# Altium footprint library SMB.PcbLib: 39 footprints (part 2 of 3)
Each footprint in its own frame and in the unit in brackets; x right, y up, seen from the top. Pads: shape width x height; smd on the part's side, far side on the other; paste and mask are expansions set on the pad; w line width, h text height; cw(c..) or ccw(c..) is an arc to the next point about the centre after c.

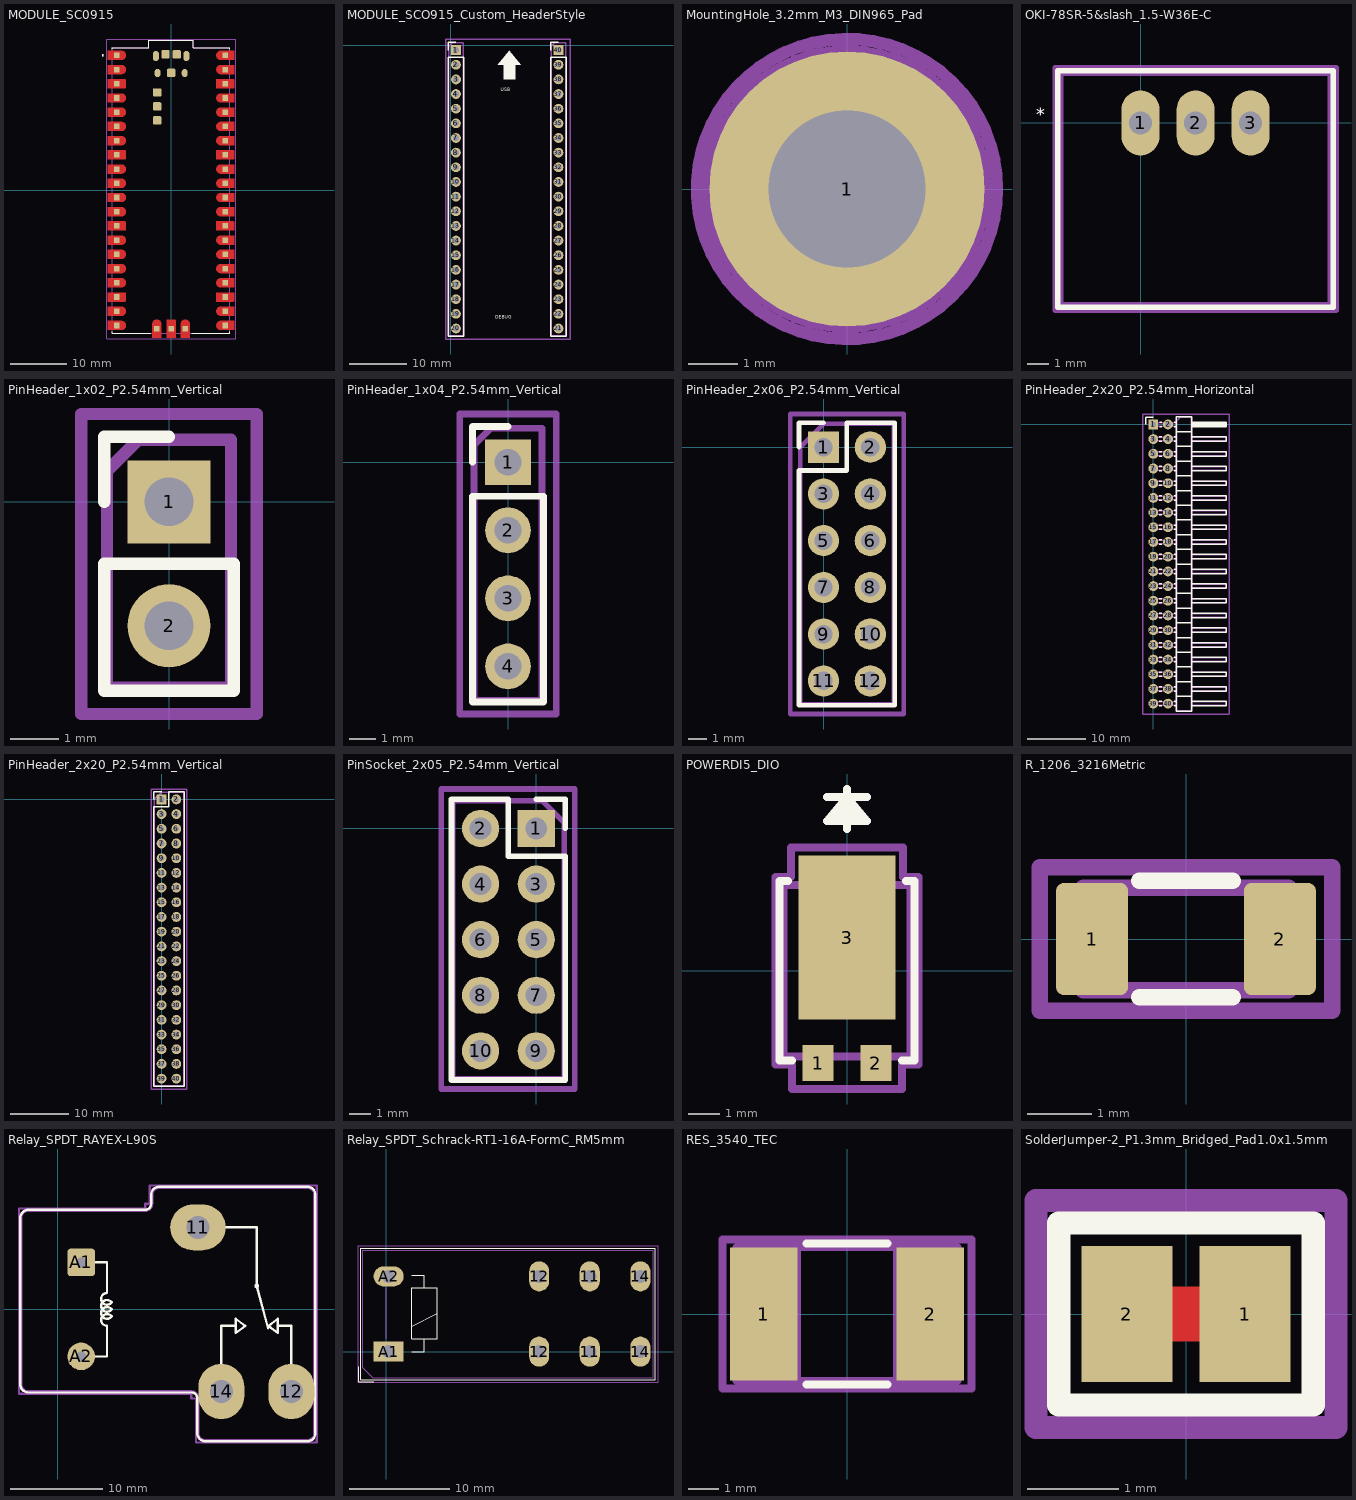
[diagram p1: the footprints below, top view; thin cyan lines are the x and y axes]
## MODULE_SC0915 [mm]
pads (53):
  rect 1x1 smd: 1(-9.69,24.13) 2(-9.69,21.59) 3(-9.69,19.05) 4(-9.69,16.51) 5(-9.69,13.97) 6(-9.69,11.43) 7(-9.69,8.89) 8(-9.69,6.35) 9(-9.69,3.81) 10(-9.69,1.27) 11(-9.69,-1.27) 12(-9.69,-3.81) 13(-9.69,-6.35) 14(-9.69,-8.89) 15(-9.69,-11.43) 16(-9.69,-13.97) 17(-9.69,-16.51) 18(-9.69,-19.05) 19(-9.69,-21.59) 20(-9.69,-24.13) 21(9.69,-24.13) 22(9.69,-21.59) 23(9.69,-19.05) 24(9.69,-16.51) 25(9.69,-13.97) 26(9.69,-11.43) 27(9.69,-8.89) 28(9.69,-6.35) 29(9.69,-3.81) 30(9.69,-1.27) 31(9.69,1.27) 32(9.69,3.81) 33(9.69,6.35) 34(9.69,8.89) 35(9.69,11.43) 36(9.69,13.97) 37(9.69,16.51) 38(9.69,19.05) 39(9.69,21.59) 40(9.69,24.13) D1(-2.54,-24.7) D2(0,-24.7) D3(2.54,-24.7)
  rrect100% 1.1x1.8 smd: A(-2.725,24) B(2.725,24)
  rrect100% 1.05x1.45 smd: C(-2.425,20.97) D(2.425,20.97)
  rrect30% 1.5x1.5 smd: TP1(0,21) TP2(1,24.3) TP3(-1,24.3) TP4(-2.5,17.5) TP5(-2.5,15) TP6(-2.5,12.5)
F.Cu:
  drawing of 43 lines, arcs and shapes, not listed
F.SilkS:
  circle w0.2: c-12.19,24.13 r0.1
  lines w0.127: -10.5,-25.25 -10.5,-25.5 -3.66,-25.5 ; -10.5,25.25 -10.5,25.5 -4,25.5 -4,26.8 4,26.8 4,25.5 10.5,25.5 10.5,25.25 ; 3.66,-25.5 10.5,-25.5 10.5,-25.25
F.Paste:
  drawing of 43 lines, arcs and shapes, not listed
F.Mask:
  drawing of 43 lines, arcs and shapes, not listed
F.Fab:
  circle w0.2: c-12.19,24.13 r0.1
  lines w0.127: -10.5,-25.5 10.5,-25.5 10.5,25.5 4,25.5 4,26.8 -4,26.8 -4,25.5 -10.5,25.5 -10.5,-25.5
F.CrtYd:
  lines w0.05: -11.54,-26.55 -11.54,27.05 11.54,27.05 11.54,-26.55 -11.54,-26.55

## MODULE_SCO915_Custom_HeaderStyle [mm]
pads (40):
  rect 1.7x1.7 hole 1: 1(0.853,-0.859) 40(18.633,-0.859)
  rrect100% 1.7x1.7 hole 1: 2(0.853,-3.399) 3(0.875,-5.95) 4(0.853,-8.479) 5(0.853,-11.019) 6(0.853,-13.559) 7(0.853,-16.099) 8(0.853,-18.639) 9(0.853,-21.179) 10(0.853,-23.719) 11(0.853,-26.259) 12(0.853,-28.799) 13(0.853,-31.339) 14(0.853,-33.879) 15(0.853,-36.419) 16(0.853,-38.959) 17(0.853,-41.499) 18(0.853,-44.039) 19(0.853,-46.579) 20(0.853,-49.119) 21(18.633,-49.119) 22(18.633,-46.579) 23(18.633,-44.039) 24(18.633,-41.499) 25(18.633,-38.959) 26(18.633,-36.419) 27(18.633,-33.879) 28(18.633,-31.339) 29(18.633,-28.799) 30(18.633,-26.259) 31(18.633,-23.719) 32(18.633,-21.179) 33(18.633,-18.639) 34(18.633,-16.099) 35(18.633,-13.559) 36(18.633,-11.019) 37(18.633,-8.479) 38(18.633,-5.939) 39(18.633,-3.399)
F.SilkS:
  region: 12.133,-3.439 11.133,-3.439 11.133,-5.939 9.133,-5.939 9.133,-3.439 8.133,-3.439 10.133,-0.939
  lines w0.254: -0.477,-0.859 -0.477,0.471 0.853,0.471 ; 17.303,-0.859 17.303,0.471 18.633,0.471 ; -0.477,-50.449 -0.477,-2.129 2.183,-2.129 2.183,-50.449 -0.477,-50.449 ; 17.303,-50.449 17.303,-2.129 19.963,-2.129 19.963,-50.449 17.303,-50.449
  text "USB" at 8.633,-8.224 h1
  text "DEBUG" at 7.633,-47.724 h1
F.Fab:
  lines w0.254: -0.417,-50.389 -0.417,-0.224 0.218,0.411 2.123,0.411 2.123,-50.389 -0.417,-50.389 ; 17.363,-50.389 17.363,-0.224 17.998,0.411 19.903,0.411 19.903,-50.389 17.363,-50.389
  text "'.Designator'" at 1.251,-26.428 h1
  text "'.Designator'" at 19.031,-26.428 h1
F.CrtYd:
  lines w0.254: -0.867,-50.939 -0.867,1.061 20.633,1.061 20.633,-50.939 -0.867,-50.939
3D body "61302011121+(rev1).stp": height 14.07, standoff 2.53, extent -0.4,-50.55 2.14,0.25
3D body "61302011121+(rev1).stp": height 14.07, standoff 2.53, extent 17.405,-50.55 19.945,0.25
3D body "61302011821+%28rev1%29.stp": height 8.55, standoff -3.06, extent 17.403,-50.624 19.903,0.676
3D body "61302011821+%28rev1%29.stp": height 8.55, standoff -3.06, extent -0.375,-50.675 2.125,0.625
3D body "SC0915.STEP": height 14.73, standoff 11, extent -0.75,-50.65 20.25,1.65

## MountingHole_3.2mm_M3_DIN965_Pad [mm]
pads (1):
  round 5.6 hole 3.2 paste-2539.97 mask+0: 1(0,0)
F.Fab:
  text "'.Designator'" at -0.271,-0.285 h1
F.CrtYd:
  circle w0.254: c0,0 r3.05
Cmts.User:
  circle w0.254: c0,0 r2.8

## OKI-78SR-5&slash_1.5-W36E-C [mm]
pads (3):
  rrect100% 1.75x3 hole 1.067: 1(0,0) 2(2.54,0) 3(5.08,0)
F.SilkS:
  lines w0.254: -3.81,-8.509 8.89,-8.509 8.89,2.413 -3.81,2.413 -3.81,-8.509
  text "*" at -4.821,-0.117 h1
  text "*" at -4.821,-0.117 h1
F.Fab:
  lines w0.254: -3.683,-8.382 8.763,-8.382 8.763,2.286 -3.683,2.286 -3.683,-8.382
  text "*" at -3.551,-0.117 h1
  text "*" at -3.551,-0.117 h1
F.CrtYd:
  lines w0.254: -3.937,-8.636 9.017,-8.636 ; -3.937,-8.636 9.017,-8.636 ; -3.937,-8.636 -3.937,2.54 ; -3.937,-8.636 -3.937,2.54 ; -3.937,2.54 9.017,2.54 ; -3.937,2.54 9.017,2.54 ; 9.017,-8.636 9.017,2.54 ; 9.017,-8.636 9.017,2.54
3D body "OKI-78SR-51_5-W36E-C_MUR.step": height 18.13, standoff -5.69, extent -3.734,-8.382 8.712,2.286

## PinHeader_1x02_P2.54mm_Vertical [mm]
pads (2):
  rect 1.7x1.7 hole 1 paste-2539.97 mask+0: 1(0,0)
  rrect100% 1.7x1.7 hole 1 paste-2539.97 mask+0: 2(0,-2.54)
F.SilkS:
  lines w0.254: -1.33,0 -1.33,1.33 0,1.33 ; -1.33,-3.87 -1.33,-1.27 1.33,-1.27 1.33,-3.87 -1.33,-3.87
F.Fab:
  lines w0.254: -1.27,-3.81 -1.27,0.635 -0.635,1.27 1.27,1.27 1.27,-3.81 -1.27,-3.81
  text "'.Designator'" at 0.361,-1.619 h1
F.CrtYd:
  lines w0.254: -1.8,-4.35 -1.8,1.8 1.8,1.8 1.8,-4.35 -1.8,-4.35

## PinHeader_1x04_P2.54mm_Vertical [mm]
pads (4):
  rect 1.7x1.7 hole 1 paste-2539.97 mask+0: 1(0,0)
  rrect100% 1.7x1.7 hole 1 paste-2539.97 mask+0: 2(0,-2.54) 3(0,-5.08) 4(0,-7.62)
F.SilkS:
  lines w0.254: -1.33,0 -1.33,1.33 0,1.33 ; -1.33,-8.95 -1.33,-1.27 1.33,-1.27 1.33,-8.95 -1.33,-8.95
F.Fab:
  lines w0.254: -1.27,-8.89 1.27,-8.89 1.27,1.27 -0.635,1.27 -1.27,0.635 -1.27,-8.89
  text "'.Designator'" at 0.363,-4.184 h1
F.CrtYd:
  lines w0.254: -1.8,-9.4 -1.8,1.8 1.8,1.8 1.8,-9.4 -1.8,-9.4

## PinHeader_2x06_P2.54mm_Vertical [mm]
pads (12):
  rect 1.7x1.7 hole 1 paste-2539.97 mask+0: 1(0,0)
  rrect100% 1.7x1.7 hole 1 paste-2539.97 mask+0: 2(2.54,0) 3(0,-2.54) 4(2.54,-2.54) 5(0,-5.08) 6(2.54,-5.08) 7(0,-7.62) 8(2.54,-7.62) 9(0,-10.16) 10(2.54,-10.16) 11(0,-12.7) 12(2.54,-12.7)
F.SilkS:
  lines w0.254: -1.33,0 -1.33,1.33 0,1.33 ; -1.33,-14.03 -1.33,-1.27 1.27,-1.27 1.27,1.33 3.87,1.33 3.87,-14.03 -1.33,-14.03
F.Fab:
  lines w0.254: -1.27,-13.97 -1.27,0 0,1.27 3.81,1.27 3.81,-13.97 -1.27,-13.97
  text "'.Designator'" at 0.909,-6.114 h1
F.CrtYd:
  lines w0.254: -1.8,-14.5 -1.8,1.8 4.35,1.8 4.35,-14.5 -1.8,-14.5

## PinHeader_2x20_P2.54mm_Horizontal [mm]
pads (40):
  rect 1.7x1.7 hole 1 paste-2539.97 mask+0: 1(0,0)
  rrect100% 1.7x1.7 hole 1 paste-2539.97 mask+0: 2(2.54,0) 3(0,-2.54) 4(2.54,-2.54) 5(0,-5.08) 6(2.54,-5.08) 7(0,-7.62) 8(2.54,-7.62) 9(0,-10.16) 10(2.54,-10.16) 11(0,-12.7) 12(2.54,-12.7) 13(0,-15.24) 14(2.54,-15.24) 15(0,-17.78) 16(2.54,-17.78) 17(0,-20.32) 18(2.54,-20.32) 19(0,-22.86) 20(2.54,-22.86) 21(0,-25.4) 22(2.54,-25.4) 23(0,-27.94) 24(2.54,-27.94) 25(0,-30.48) 26(2.54,-30.48) 27(0,-33.02) 28(2.54,-33.02) 29(0,-35.56) 30(2.54,-35.56) 31(0,-38.1) 32(2.54,-38.1) 33(0,-40.64) 34(2.54,-40.64) 35(0,-43.18) 36(2.54,-43.18) 37(0,-45.72) 38(2.54,-45.72) 39(0,-48.26) 40(2.54,-48.26)
F.SilkS:
  drawing of 171 lines, arcs and shapes, not listed
F.Fab:
  lines w0.254: 4.04,-48.58 -0.32,-48.58 -0.32,-47.94 4.04,-47.94 ; 4.04,-46.04 -0.32,-46.04 -0.32,-45.4 4.04,-45.4 ; 4.04,-43.5 -0.32,-43.5 -0.32,-42.86 4.04,-42.86 ; 4.04,-40.96 -0.32,-40.96 -0.32,-40.32 4.04,-40.32 ; 4.04,-38.42 -0.32,-38.42 -0.32,-37.78 4.04,-37.78 ; 4.04,-35.88 -0.32,-35.88 -0.32,-35.24 4.04,-35.24 ; 4.04,-33.34 -0.32,-33.34 -0.32,-32.7 4.04,-32.7 ; 4.04,-30.8 -0.32,-30.8 -0.32,-30.16 4.04,-30.16 ; 4.04,-28.26 -0.32,-28.26 -0.32,-27.62 4.04,-27.62 ; 4.04,-25.72 -0.32,-25.72 -0.32,-25.08 4.04,-25.08 ; 4.04,-23.18 -0.32,-23.18 -0.32,-22.54 4.04,-22.54 ; 4.04,-20.64 -0.32,-20.64 -0.32,-20 4.04,-20 ; 4.04,-18.1 -0.32,-18.1 -0.32,-17.46 4.04,-17.46 ; 4.04,-15.56 -0.32,-15.56 -0.32,-14.92 4.04,-14.92 ; 4.04,-13.02 -0.32,-13.02 -0.32,-12.38 4.04,-12.38 ; 4.04,-10.48 -0.32,-10.48 -0.32,-9.84 4.04,-9.84 ; 4.04,-7.94 -0.32,-7.94 -0.32,-7.3 4.04,-7.3 ; 4.04,-5.4 -0.32,-5.4 -0.32,-4.76 4.04,-4.76 ; 4.04,-2.86 -0.32,-2.86 -0.32,-2.22 4.04,-2.22 ; 4.04,-0.32 -0.32,-0.32 -0.32,0.32 4.04,0.32 ; 6.58,-48.58 12.58,-48.58 12.58,-47.94 6.58,-47.94 ; 6.58,-46.04 12.58,-46.04 12.58,-45.4 6.58,-45.4 ; 6.58,-43.5 12.58,-43.5 12.58,-42.86 6.58,-42.86 ; 6.58,-40.96 12.58,-40.96 12.58,-40.32 6.58,-40.32 ; 6.58,-38.42 12.58,-38.42 12.58,-37.78 6.58,-37.78 ; 6.58,-35.88 12.58,-35.88 12.58,-35.24 6.58,-35.24 ; 6.58,-33.34 12.58,-33.34 12.58,-32.7 6.58,-32.7 ; 6.58,-30.8 12.58,-30.8 12.58,-30.16 6.58,-30.16 ; 6.58,-28.26 12.58,-28.26 12.58,-27.62 6.58,-27.62 ; 6.58,-25.72 12.58,-25.72 12.58,-25.08 6.58,-25.08 ; 6.58,-23.18 12.58,-23.18 12.58,-22.54 6.58,-22.54 ; 6.58,-20.64 12.58,-20.64 12.58,-20 6.58,-20 ; 6.58,-18.1 12.58,-18.1 12.58,-17.46 6.58,-17.46 ; 6.58,-15.56 12.58,-15.56 12.58,-14.92 6.58,-14.92 ; 6.58,-13.02 12.58,-13.02 12.58,-12.38 6.58,-12.38 ; 6.58,-10.48 12.58,-10.48 12.58,-9.84 6.58,-9.84 ; 6.58,-7.94 12.58,-7.94 12.58,-7.3 6.58,-7.3 ; 6.58,-5.4 12.58,-5.4 12.58,-4.76 6.58,-4.76 ; 6.58,-2.86 12.58,-2.86 12.58,-2.22 6.58,-2.22 ; 6.58,-0.32 12.58,-0.32 12.58,0.32 6.58,0.32 ; 4.04,-49.53 6.58,-49.53 6.58,1.27 4.675,1.27 4.04,0.635 4.04,-49.53
  text "'.Designator'" at 5.671,-24.362 h1
F.CrtYd:
  lines w0.254: -1.8,-50.05 13.1,-50.05 13.1,1.8 -1.8,1.8 -1.8,-50.05
3D body "XG4A-4035--3DModel-STEP-273799.STEP": height 8.5, standoff -2.9, extent -1.143,-59.18 22.157,10.92

## PinHeader_2x20_P2.54mm_Vertical [mm]
pads (40):
  rect 1.7x1.7 hole 1 paste-2539.97 mask+0: 1(0,0)
  rrect100% 1.7x1.7 hole 1 paste-2539.97 mask+0: 2(2.54,0) 3(0,-2.54) 4(2.54,-2.54) 5(0,-5.08) 6(2.54,-5.08) 7(0,-7.62) 8(2.54,-7.62) 9(0,-10.16) 10(2.54,-10.16) 11(0,-12.7) 12(2.54,-12.7) 13(0,-15.24) 14(2.54,-15.24) 15(0,-17.78) 16(2.54,-17.78) 17(0,-20.32) 18(2.54,-20.32) 19(0,-22.86) 20(2.54,-22.86) 21(0,-25.4) 22(2.54,-25.4) 23(0,-27.94) 24(2.54,-27.94) 25(0,-30.48) 26(2.54,-30.48) 27(0,-33.02) 28(2.54,-33.02) 29(0,-35.56) 30(2.54,-35.56) 31(0,-38.1) 32(2.54,-38.1) 33(0,-40.64) 34(2.54,-40.64) 35(0,-43.18) 36(2.54,-43.18) 37(0,-45.72) 38(2.54,-45.72) 39(0,-48.26) 40(2.54,-48.26)
F.SilkS:
  lines w0.254: -1.33,0 -1.33,1.33 0,1.33 ; -1.33,-49.59 3.87,-49.59 3.87,1.33 1.27,1.33 1.27,-1.27 -1.33,-1.27 -1.33,-49.59
F.Fab:
  lines w0.254: -1.27,-49.53 3.81,-49.53 3.81,1.27 0,1.27 -1.27,0 -1.27,-49.53
  text "'.Designator'" at 1.631,-24.475 h1
F.CrtYd:
  lines w0.254: -1.8,-50.05 4.35,-50.05 4.35,1.8 -1.8,1.8 -1.8,-50.05

## PinSocket_2x05_P2.54mm_Vertical [mm]
pads (10):
  rect 1.7x1.7 hole 1 paste-2539.97 mask+0: 1(0,0)
  rrect100% 1.7x1.7 hole 1 paste-2539.97 mask+0: 2(-2.54,0) 3(0,-2.54) 4(-2.54,-2.54) 5(0,-5.08) 6(-2.54,-5.08) 7(0,-7.62) 8(-2.54,-7.62) 9(0,-10.16) 10(-2.54,-10.16)
F.SilkS:
  lines w0.254: 0,1.33 1.33,1.33 1.33,0 ; -3.87,-11.49 -3.87,1.33 -1.27,1.33 -1.27,-1.27 1.33,-1.27 1.33,-11.49 -3.87,-11.49
F.Fab:
  lines w0.254: -3.81,-11.43 -3.81,1.27 0.27,1.27 1.27,0.27 1.27,-11.43 -3.81,-11.43
  text "'.Designator'" at -0.907,-5.461 h1
F.CrtYd:
  lines w0.254: -4.34,-11.9 -4.34,1.8 1.76,1.8 1.76,-11.9 -4.34,-11.9

## POWERDI5_DIO [mil]
pads (3):
  rect 39x45 smd: 1(-36.22,-115.5) 2(36.22,-115.5)
  rect 122x205 smd: 3(0,41.5)
F.SilkS:
  lines w10: -74.1,112.5 -84.5,112.5 -84.5,-112.5 -68.82,-112.5 ; -25,217.5 25,217.5 ; -20,187.5 0,217.5 ; -15,187.5 0,217.5 ; -10,187.5 0,217.5 ; -5,187.5 0,217.5 ; 0,177.5 0,227.5 ; 5,187.5 0,217.5 ; 10,187.5 0,217.5 ; 15,187.5 0,217.5 ; 20,187.5 0,217.5 ; 68.82,-112.5 84.5,-112.5 84.5,112.5 74.1,112.5 ; 0,217.5 -25,187.5 25,187.5 0,217.5
F.Fab:
  lines w10: -25,217.5 25,217.5 ; -20,187.5 0,217.5 ; -15,187.5 0,217.5 ; -10,187.5 0,217.5 ; -5,187.5 0,217.5 ; 0,177.5 0,227.5 ; 5,187.5 0,217.5 ; 10,187.5 0,217.5 ; 15,187.5 0,217.5 ; 20,187.5 0,217.5 ; 0,217.5 -25,187.5 25,187.5 0,217.5 ; -79.5,-107.5 -79.5,107.5 79.5,107.5 79.5,-107.5 -79.5,-107.5
  text "'.Designator'" at -56.64,-15.69 h39.37
F.CrtYd:
  lines w10: -89.5,-117.5 -89.5,117.5 -70,117.5 -70,154 70,154 70,117.5 89.5,117.5 89.5,-117.5 68.72,-117.5 68.72,-148 -68.72,-148 -68.72,-117.5 -89.5,-117.5
3D body "POWERDI5_DIO.step": height 47.09, standoff 0, extent -77.49,-128 81.49,132

## R_1206_3216Metric [mm]
pads (2):
  rrect22% 1.125x1.75 smd mask+0: 1(-1.462,0) 2(1.462,0)
F.SilkS:
  lines w0.254: -0.727,-0.91 0.727,-0.91 ; -0.727,0.91 0.727,0.91
F.Fab:
  lines w0.254: -1.6,-0.8 -1.6,0.8 1.6,0.8 1.6,-0.8 -1.6,-0.8
  text "'.Designator'" at 0.209,0.224 h0.8
F.CrtYd:
  lines w0.254: -2.28,-1.12 -2.28,1.12 2.28,1.12 2.28,-1.12 -2.28,-1.12

## Relay_SPDT_RAYEX-L90S [mm]
pads (5):
  rrect100% 6x5 hole 2.5: 11(15.2,8.9)
  rrect100% 5x6 hole 2.5: 12(25.34,-8.9) 14(17.74,-8.9)
  rrect25% 3x3 hole 1.1: A1(2.54,5.1)
  round 3 hole 1.1: A2(2.54,-5.1)
F.SilkS:
  circle w0.254: c21.59,2.54 r0.127
  lines w0.254: 4.064,-5.105 5.334,-5.105 5.334,-1.778 cw(c5.334,-1.143) 5.842,-0.762 cw(c5.334,-0.381) 5.842,0 cw(c5.334,0.381) 5.842,0.762 cw(c5.334,1.143) 5.334,1.778 5.334,5.105 4.064,5.105 ; 17.526,8.9 21.59,8.9 21.59,2.54 22.809,-2.032 ; 17.74,-6.604 17.74,-1.778 19.304,-1.778 ; 23.876,-1.778 25.34,-1.778 25.34,-6.604 ; -4.07,-8.14 ccw(c-3.2,-8.14) -3.2,-9.01 14.48,-9.01 cw(c14.48,-9.66) 15.13,-9.66 15.13,-13.44 ccw(c16,-13.44) 16,-14.31 27.08,-14.31 ccw(c27.08,-13.44) 27.95,-13.44 27.95,12.44 ccw(c27.08,12.44) 27.08,13.31 11,13.31 ccw(c11,12.44) 10.13,12.44 10.13,11.46 cw(c9.48,11.46) 9.48,10.81 -3.2,10.81 ccw(c-3.2,9.94) -4.07,9.94 -4.07,-8.14 ; 19.304,-2.54 20.32,-1.778 19.304,-1.016 19.304,-2.54 ; 22.86,-1.778 23.876,-2.54 23.876,-1.016 22.86,-1.778
F.Fab:
  lines w0.254: -3.96,-8.14 ccw(c-3.2,-8.14) -3.2,-8.9 14.48,-8.9 cw(c14.48,-9.66) 15.24,-9.66 15.24,-13.44 ccw(c16,-13.44) 16,-14.2 27.08,-14.2 ccw(c27.08,-13.44) 27.84,-13.44 27.84,12.44 ccw(c27.08,12.44) 27.08,13.2 11,13.2 ccw(c11,12.44) 10.24,12.44 10.24,11.46 cw(c9.48,11.46) 9.48,10.7 -3.2,10.7 ccw(c-3.2,9.94) -3.96,9.94 -3.96,-8.14
  text "'.Designator'" at 10.957,-0.398 h1
F.CrtYd:
  lines w0.254: -4.21,-9.15 14.48,-9.15 14.48,-9.66 14.99,-9.66 14.99,-14.45 28.09,-14.45 28.09,13.45 9.99,13.45 9.99,11.46 9.48,11.46 9.48,10.95 -4.21,10.95 -4.21,-9.15
3D body "50A relay.STEP": height 20, standoff -4, extent -4.466,-14.287 27.584,12.713

## Relay_SPDT_Schrack-RT1-16A-FormC_RM5mm [mm]
pads (8):
  rrect100% 2x3 hole 1.3: 11(20.3,0) 11(20.3,7.5) 12(15.26,0) 12(15.26,7.5) 14(25.34,0) 14(25.34,7.5)
  rect 3x2 hole 1.3: A1(0.25,0)
  rrect100% 3x2 hole 1.3: A2(0.25,7.5)
F.SilkS:
  lines w0.1: 2.54,2.54 5.08,3.81
  lines w0.12: -2.75,-1.5 -2.75,-3 -1.25,-3 ; 2.54,0 3.81,0 3.81,1.27 ; 2.54,7.62 3.81,7.62 3.81,6.35 ; 3.81,1.27 2.54,1.27 2.54,6.35 5.08,6.35 5.08,1.27 3.81,1.27 ; -2.55,-2.8 -2.55,10.3 26.85,10.3 26.85,-2.8 -2.55,-2.8
F.Fab:
  lines w0.1: -2.35,-1.6 -1.35,-2.6 26.65,-2.6 26.65,10.1 -2.35,10.1 -2.35,-1.6
  lines w0.12: 0,1.27 0,6.35
  text "'.Designator'" at 10.626,3.412 h1
F.CrtYd:
  lines w0.05: -2.8,-3.05 27.1,-3.05 27.1,10.55 -2.8,10.55 -2.8,-3.05

## RES_3540_TEC [mil]
pads (2):
  rect 87x173 smd: 1(-108,0) 2(108,0)
F.SilkS:
  lines w10: -52.39,-91.5 52.39,-91.5 ; -52.39,91.5 52.39,91.5
F.Fab:
  lines w10: -143.5,-86.5 -143.5,86.5 ; -143.5,-86.5 -143.5,86.5 ; -143.5,-86.5 -64.5,-86.5 -64.5,86.5 -143.5,86.5 ; -143.5,-86.5 143.5,-86.5 ; -143.5,86.5 143.5,86.5 ; 143.5,-86.5 64.5,-86.5 64.5,86.5 143.5,86.5 ; 143.5,-86.5 143.5,86.5 ; 143.5,-86.5 143.5,86.5
  text "'.Designator'" at -56.64,-15.69 h39.37
F.CrtYd:
  lines w10: -161.5,-96.5 -161.5,96.5 161.5,96.5 161.5,-96.5 -161.5,-96.5
3D body "RES_3540_TEC.step": height 47.01, standoff 0, extent -142.5,-86.5 144.5,86.5

## SolderJumper-2_P1.3mm_Bridged_Pad1.0x1.5mm [mm]
pads (2):
  rect 1x1.5 smd paste-1.5 mask+0: 1(0.65,0) 2(-0.65,0)
F.Cu:
  region: -0.25,-0.3 0.25,-0.3 0.25,0.3 -0.25,0.3
F.SilkS:
  lines w0.254: -1.4,-1 1.4,-1 1.4,1 -1.4,1 -1.4,-1
B.CrtYd:
  lines w0.254: -1.65,-1.25 1.65,-1.25 1.65,1.25 -1.65,1.25 -1.65,-1.25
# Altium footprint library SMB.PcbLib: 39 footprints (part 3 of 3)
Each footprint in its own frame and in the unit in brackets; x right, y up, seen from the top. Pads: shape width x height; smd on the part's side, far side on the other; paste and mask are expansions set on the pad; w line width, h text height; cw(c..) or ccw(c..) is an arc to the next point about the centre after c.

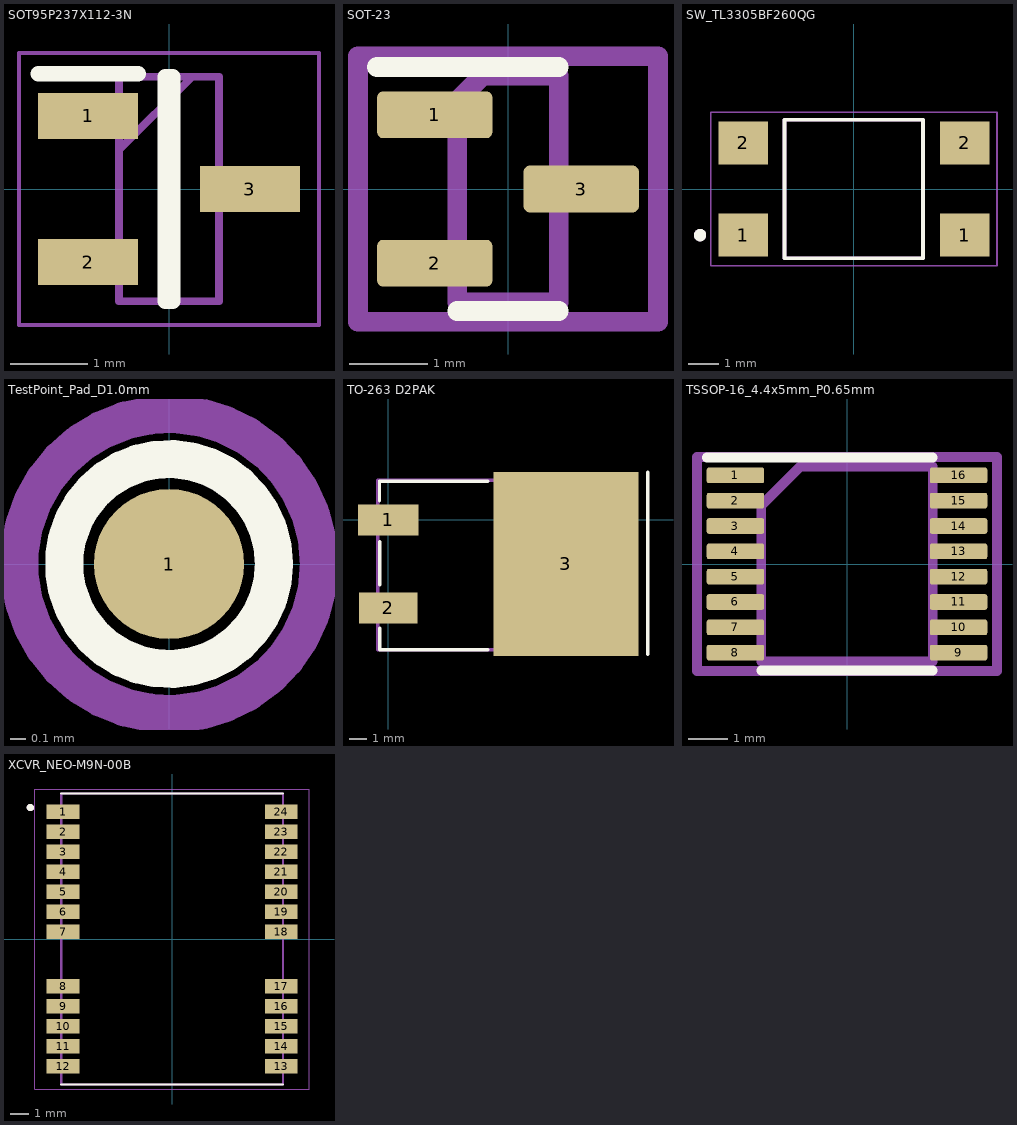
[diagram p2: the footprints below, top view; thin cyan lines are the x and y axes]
## SOT95P237X112-3N [mm]
pads (3):
  rect 1.3x0.6 smd: 1(-1.05,0.95) 2(-1.05,-0.95) 3(1.05,0)
F.SilkS:
  lines w0.2: -1.7,1.5 -0.4,1.5 ; -0.05,-1.46 0.05,-1.46 0.05,1.46 -0.05,1.46 -0.05,-1.46
F.Fab:
  lines w0.05: -1.95,-1.77 -1.95,1.77 1.95,1.77 1.95,-1.77 -1.95,-1.77
  lines w0.1: -0.65,0.51 0.3,1.46 ; -0.65,-1.46 0.65,-1.46 0.65,1.46 -0.65,1.46 -0.65,-1.46

## SOT-23 [mm]
pads (3):
  rrect25% 1.475x0.6 smd mask+0: 1(-0.937,0.95) 2(-0.937,-0.95) 3(0.937,0)
F.SilkS:
  lines w0.254: -1.675,1.56 0,1.56 0.65,1.56 ; -0.65,-1.56 0,-1.56 0.65,-1.56
F.Fab:
  lines w0.254: -0.65,-1.45 -0.65,1.125 -0.325,1.45 0.65,1.45 0.65,-1.45 -0.65,-1.45
  text "'.Designator'" at -0.089,-0.09 h0.32
F.CrtYd:
  lines w0.254: -1.92,-1.7 1.92,-1.7 1.92,1.7 -1.92,1.7 -1.92,-1.7

## SW_TL3305BF260QG [mm]
pads (4):
  rect 1.6x1.4 smd: 1(-3.6,-1.5) 1(3.6,-1.5) 2(-3.6,1.5) 2(3.6,1.5)
F.SilkS:
  circle w0.2: c-5,-1.5 r0.1
  lines w0.127: -2.25,-2.25 2.25,-2.25 2.25,2.25 -2.25,2.25 -2.25,-2.25
F.Fab:
  circle w0.2: c-5,-1.5 r0.1
  lines w0.127: -2.25,-2.25 -2.25,2.25 2.25,2.25 2.25,-2.25 -2.25,-2.25
F.CrtYd:
  lines w0.05: -4.65,-2.5 -4.65,2.5 4.65,2.5 4.65,-2.5 -4.65,-2.5
3D body "TL3305BF260QG.step": height 5, standoff 0, extent -3.725,-2.25 3.775,2.25

## TestPoint_Pad_D1.0mm [mm]
pads (1):
  round 1 smd paste-1 mask+0: 1(0,0)
F.SilkS:
  circle w0.254: c0,0 r0.7
F.Fab:
  text "'.Designator'" at 0.116,1.732 h1
F.CrtYd:
  circle w0.254: c0,0 r1

## TO-263 D2PAK [mm]
pads (3):
  rect 3.5x1.8 smd: 1(0,0)
  rect 3.4x1.8 smd: 2(0,-5.08)
  rect 8.38x10.66 smd: 3(10.26,-2.545)
F.SilkS:
  lines w0.2: -0.507,1.121 -0.507,2.243 ; -0.5,-6.25 -0.5,-7.5 5.75,-7.5 ; -0.5,-3.75 -0.5,-1.25 ; 5.743,2.243 -0.507,2.243 ; 15,-7.75 15,2.75 ; -0.507,2.243 -0.507,2.243
Mechanical 1:
  lines w0.2: -0.6,-7.5 14,-7.5 14,2.3 -0.6,2.3 -0.6,-7.5
  text ".Designator" at 0.2,-3.067 h1
3D body "TO263-2-1.stp": height 4.22, standoff 0, extent -0.585,-7.518 14.001,2.303

## TSSOP-16_4.4x5mm_P0.65mm [mm]
pads (16):
  rrect25% 1.475x0.4 smd mask+0: 1(-2.863,2.275) 2(-2.863,1.625) 3(-2.863,0.975) 4(-2.863,0.325) 5(-2.863,-0.325) 6(-2.863,-0.975) 7(-2.863,-1.625) 8(-2.863,-2.275) 9(2.863,-2.275) 10(2.863,-1.625) 11(2.863,-0.975) 12(2.863,-0.325) 13(2.863,0.325) 14(2.863,0.975) 15(2.863,1.625) 16(2.863,2.275)
F.SilkS:
  lines w0.254: -3.6,2.735 0,2.735 2.2,2.735 ; -2.2,-2.735 0,-2.735 2.2,-2.735
F.Fab:
  lines w0.254: -2.2,-2.5 -2.2,1.5 -1.2,2.5 2.2,2.5 2.2,-2.5 -2.2,-2.5
  text "'.Designator'" at 0.274,0.282 h1
F.CrtYd:
  lines w0.254: -3.85,-2.75 -3.85,2.75 3.85,2.75 3.85,-2.75 -3.85,-2.75

## XCVR_NEO-M9N-00B [mm]
pads (24):
  rect 1.8x0.8 smd: 1(-6,7) 2(-6,5.9) 3(-6,4.8) 4(-6,3.7) 5(-6,2.6) 6(-6,1.5) 7(-6,0.4) 8(-6,-2.6) 9(-6,-3.7) 10(-6,-4.8) 11(-6,-5.9) 12(-6,-7) 13(6,-7) 14(6,-5.9) 15(6,-4.8) 16(6,-3.7) 17(6,-2.6) 18(6,0.4) 19(6,1.5) 20(6,2.6) 21(6,3.7) 22(6,4.8) 23(6,5.9) 24(6,7)
F.SilkS:
  circle w0.2: c-7.8,7.23 r0.1
  lines w0.127: -6.1,-8 6.1,-8 ; -6.1,8 6.1,8
F.Paste:
  drawing of 24 lines, arcs and shapes, not listed
F.Fab:
  circle w0.2: c-7.8,7.23 r0.1
  lines w0.127: -6.1,-8 6.1,-8 6.1,8 -6.1,8 -6.1,-8
F.CrtYd:
  lines w0.05: -7.55,-8.25 -7.55,8.25 7.55,8.25 7.55,-8.25 -7.55,-8.25
3D body "User Library-neo-m8n.step": height 2.5, standoff 0.1, extent -5.69,-8 6.51,8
